VERSION 5.8 ;
BUSBITCHARS "[]" ;
DIVIDERCHAR "/" ;

# R1 pad ring reference abstract (empty core). Units um. Pins: bondpad TopMetal2 squares (70 x 70 um).
# Core window and ring: see README. Obstructions: core power ring (TopMetal1 / TopMetal2).

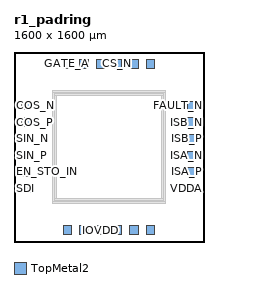
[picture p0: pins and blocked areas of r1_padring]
MACRO r1_padring
  CLASS BLOCK ;
  ORIGIN 0 0 ;
  FOREIGN r1_padring 0 0 ;
  SIZE 1600 BY 1600 ;
  SYMMETRY X Y ;
  PIN VDD
    DIRECTION INOUT ;
    USE POWER ;
    PORT
      LAYER TopMetal2 ;
        RECT 415.000 66.000 485.000 136.000 ;
    END
  END VDD
  PIN VSS
    DIRECTION INOUT ;
    USE GROUND ;
    PORT
      LAYER TopMetal2 ;
        RECT 555.000 66.000 625.000 136.000 ;
        RECT 975.000 66.000 1045.000 136.000 ;
    END
  END VSS
  PIN IOVDD
    DIRECTION INOUT ;
    USE POWER ;
    PORT
      LAYER TopMetal2 ;
        RECT 695.000 66.000 765.000 136.000 ;
    END
  END IOVDD
  PIN IOVSS
    DIRECTION INOUT ;
    USE GROUND ;
    PORT
      LAYER TopMetal2 ;
        RECT 835.000 66.000 905.000 136.000 ;
        RECT 1115.000 66.000 1185.000 136.000 ;
    END
  END IOVSS
  PIN VDDA
    DIRECTION INOUT ;
    USE POWER ;
    PORT
      LAYER TopMetal2 ;
        RECT 1464.000 415.000 1534.000 485.000 ;
    END
  END VDDA
  PIN ISA_P
    DIRECTION INOUT ;
    USE SIGNAL ;
    PORT
      LAYER TopMetal2 ;
        RECT 1464.000 555.000 1534.000 625.000 ;
    END
  END ISA_P
  PIN ISA_N
    DIRECTION INOUT ;
    USE SIGNAL ;
    PORT
      LAYER TopMetal2 ;
        RECT 1464.000 695.000 1534.000 765.000 ;
    END
  END ISA_N
  PIN ISB_P
    DIRECTION INOUT ;
    USE SIGNAL ;
    PORT
      LAYER TopMetal2 ;
        RECT 1464.000 835.000 1534.000 905.000 ;
    END
  END ISB_P
  PIN ISB_N
    DIRECTION INOUT ;
    USE SIGNAL ;
    PORT
      LAYER TopMetal2 ;
        RECT 1464.000 975.000 1534.000 1045.000 ;
    END
  END ISB_N
  PIN FAULT_N
    DIRECTION INOUT ;
    USE SIGNAL ;
    PORT
      LAYER TopMetal2 ;
        RECT 1464.000 1115.000 1534.000 1185.000 ;
    END
  END FAULT_N
  PIN GATE_A
    DIRECTION INOUT ;
    USE SIGNAL ;
    PORT
      LAYER TopMetal2 ;
        RECT 415.000 1464.000 485.000 1534.000 ;
    END
  END GATE_A
  PIN GATE_B
    DIRECTION INOUT ;
    USE SIGNAL ;
    PORT
      LAYER TopMetal2 ;
        RECT 555.000 1464.000 625.000 1534.000 ;
    END
  END GATE_B
  PIN GATE_C
    DIRECTION INOUT ;
    USE SIGNAL ;
    PORT
      LAYER TopMetal2 ;
        RECT 695.000 1464.000 765.000 1534.000 ;
    END
  END GATE_C
  PIN CS_N
    DIRECTION INOUT ;
    USE SIGNAL ;
    PORT
      LAYER TopMetal2 ;
        RECT 835.000 1464.000 905.000 1534.000 ;
    END
  END CS_N
  PIN MA_SCLK
    DIRECTION INOUT ;
    USE SIGNAL ;
    PORT
      LAYER TopMetal2 ;
        RECT 975.000 1464.000 1045.000 1534.000 ;
    END
  END MA_SCLK
  PIN SLO_SDO
    DIRECTION INOUT ;
    USE SIGNAL ;
    PORT
      LAYER TopMetal2 ;
        RECT 1115.000 1464.000 1185.000 1534.000 ;
    END
  END SLO_SDO
  PIN SDI
    DIRECTION INOUT ;
    USE SIGNAL ;
    PORT
      LAYER TopMetal2 ;
        RECT 66.000 415.000 136.000 485.000 ;
    END
  END SDI
  PIN EN_STO_IN
    DIRECTION INOUT ;
    USE SIGNAL ;
    PORT
      LAYER TopMetal2 ;
        RECT 66.000 555.000 136.000 625.000 ;
    END
  END EN_STO_IN
  PIN SIN_P
    DIRECTION INOUT ;
    USE SIGNAL ;
    PORT
      LAYER TopMetal2 ;
        RECT 66.000 695.000 136.000 765.000 ;
    END
  END SIN_P
  PIN SIN_N
    DIRECTION INOUT ;
    USE SIGNAL ;
    PORT
      LAYER TopMetal2 ;
        RECT 66.000 835.000 136.000 905.000 ;
    END
  END SIN_N
  PIN COS_P
    DIRECTION INOUT ;
    USE SIGNAL ;
    PORT
      LAYER TopMetal2 ;
        RECT 66.000 975.000 136.000 1045.000 ;
    END
  END COS_P
  PIN COS_N
    DIRECTION INOUT ;
    USE SIGNAL ;
    PORT
      LAYER TopMetal2 ;
        RECT 66.000 1115.000 136.000 1185.000 ;
    END
  END COS_N
  OBS
    LAYER TopMetal1 ;
      RECT 324.820 321.000 339.820 1279.000 ;
      RECT 344.820 321.000 361.800 1279.000 ;
      RECT 1240.420 321.000 1255.420 1279.000 ;
      RECT 1260.420 321.000 1275.420 1279.000 ;
      RECT 1240.420 347.160 1255.420 1252.300 ;
      RECT 344.820 347.160 359.820 1252.300 ;
      RECT 1260.420 327.160 1275.420 1272.300 ;
      RECT 324.820 327.160 339.820 1272.300 ;
    LAYER TopMetal2 ;
      RECT 344.820 1237.300 1255.420 1252.300 ;
      RECT 344.820 347.160 1255.420 362.160 ;
      RECT 328.000 1257.300 1272.000 1272.300 ;
      RECT 328.000 327.160 1272.000 342.160 ;
  END
END r1_padring

END LIBRARY
